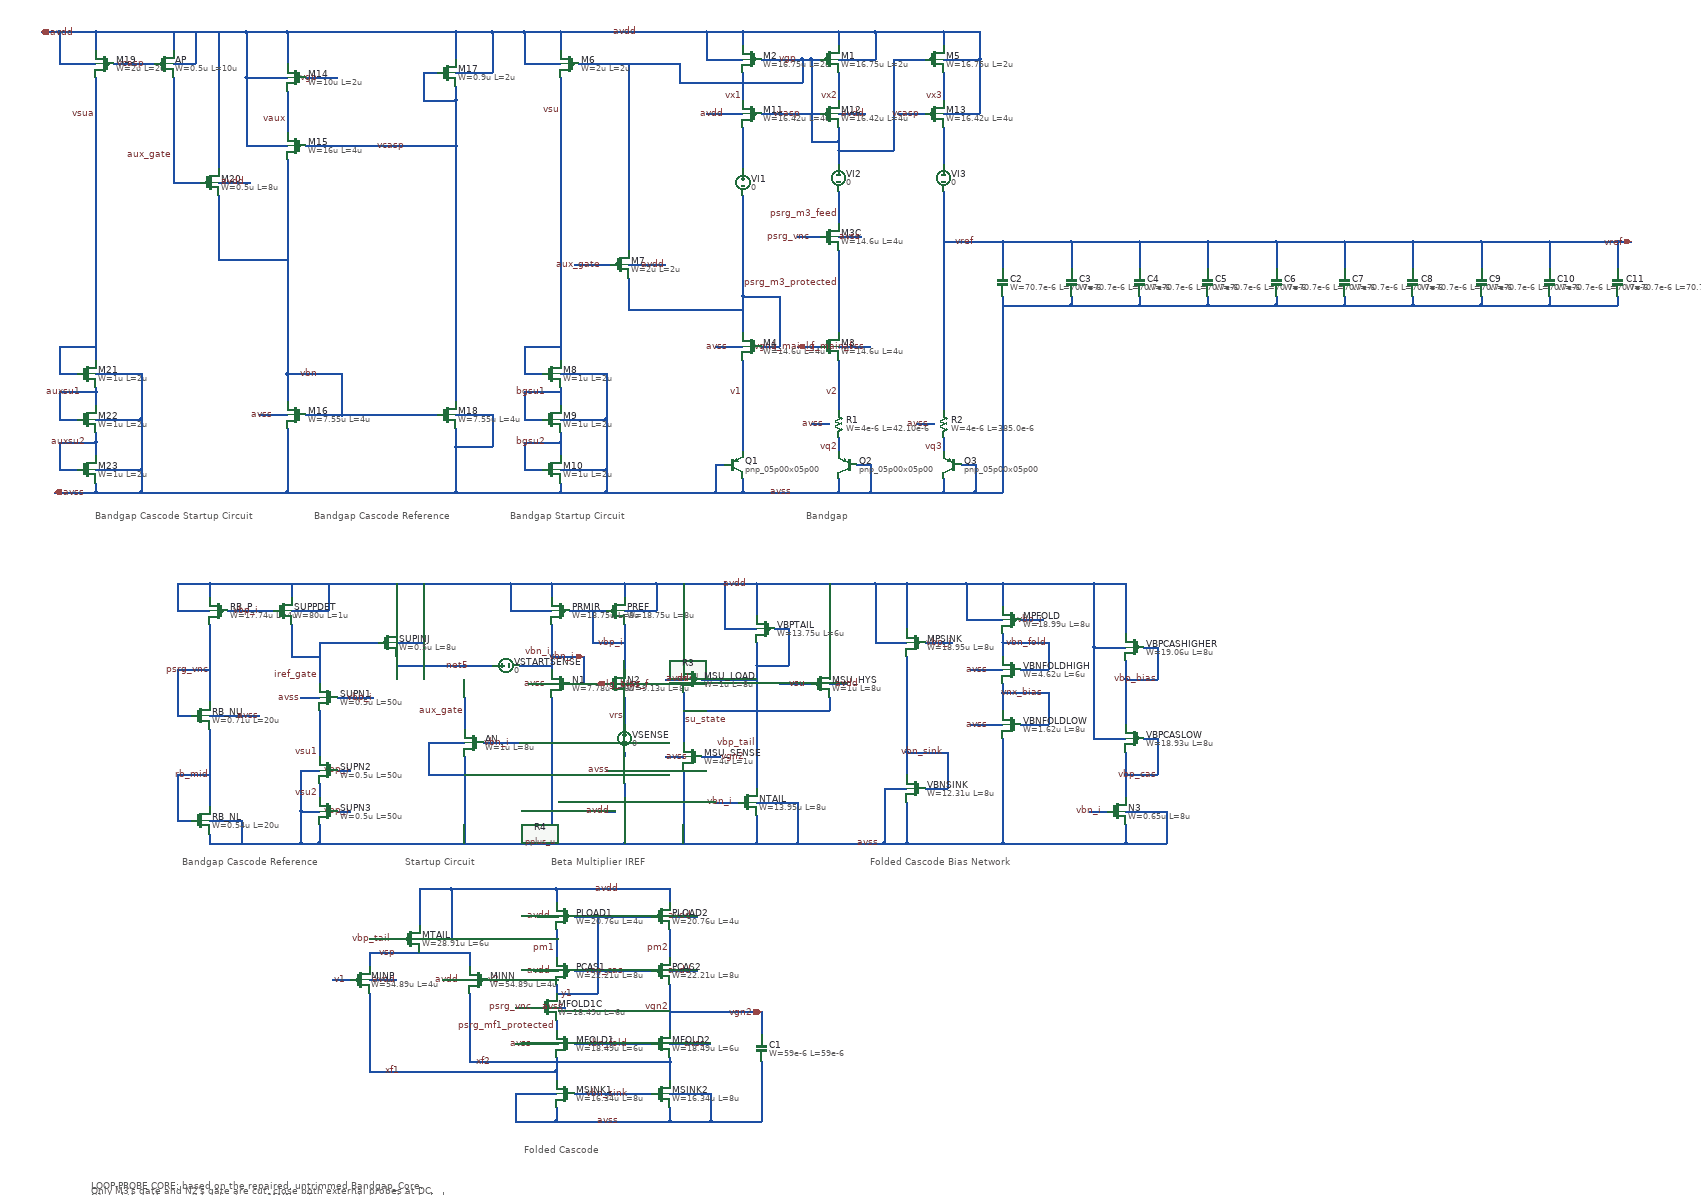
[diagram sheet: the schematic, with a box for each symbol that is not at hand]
v {xschem version=3.4.8RC file_version=1.3}
G {}
K {}
V {}
S {}
F {}
E {}
P 4 1 -1110 -640 {}
T {Bandgap} 570 440 0 0 0.4 0.4 {}
T {Bandgap Startup Circuit} -80 440 0 0 0.4 0.4 {}
T {Bandgap Cascode Reference} -510 440 0 0 0.4 0.4 {}
T {Bandgap Cascode Startup Circuit} -990 440 0 0 0.4 0.4 {}
T {Folded Cascode} -50 1830 0 0 0.4 0.4 {}
T {Folded Cascode Bias Network} 710 1200 0 0 0.4 0.4 {}
T {Beta Multiplier IREF} 10 1200 0 0 0.4 0.4 {}
T {Bandgap Cascode Reference
} -800 1200 0 0 0.4 0.4 {}
T {Startup Circuit} -310 1200 0 0 0.4 0.4 {}
N 580 -550 600 -550 {lab=vgp}
N 640 -550 720 -550 {lab=avdd}
N 720 -610 720 -550 {lab=avdd}
N 640 -610 720 -610 {lab=avdd}
N 640 -610 640 -580 {lab=avdd}
N 350 -550 430 -550 {lab=avdd}
N 350 -610 430 -610 {lab=avdd}
N 430 -610 430 -580 {lab=avdd}
N 350 -610 350 -550 {lab=avdd}
N 870 -550 950 -550 {lab=avdd}
N 870 -610 950 -610 {lab=avdd}
N 510 20 510 80 {lab=vgn1}
N 640 -350 760 -350 {lab=vgp}
N 430 370 430 400 {lab=avss}
N 430 400 640 400 {lab=avss}
N 640 370 640 400 {lab=avss}
N 710 400 870 400 {lab=avss}
N 870 370 870 400 {lab=avss}
N 680 340 710 340 {lab=avss}
N 710 340 710 400 {lab=avss}
N 370 400 430 400 {lab=avss}
N 370 340 370 400 {lab=avss}
N 370 340 390 340 {lab=avss}
N 870 400 940 400 {lab=avss}
N 940 340 940 400 {lab=avss}
N 910 340 940 340 {lab=avss}
N 370 80 430 80 {lab=avss}
N 640 80 710 80 {lab=avss}
N 30 -610 350 -610 {lab=avdd}
N 30 -610 30 -570 {lab=avdd}
N 70 -540 160 -540 {lab=vgp}
N 30 -510 30 -490 {lab=vsu}
N 160 -540 290 -540 {lab=vgp}
N 290 -540 290 -500 {lab=vgp}
N 290 -500 560 -500 {lab=vgp}
N -50 140 -10 140 {lab=vsu}
N -50 80 -50 140 {lab=vsu}
N 30 -170 30 110 {lab=vsu}
N -50 240 -10 240 {lab=bgsu1}
N -50 180 -50 240 {lab=bgsu1}
N -50 180 30 180 {lab=bgsu1}
N 30 180 30 210 {lab=bgsu1}
N -50 350 -10 350 {lab=bgsu2}
N -50 290 -50 350 {lab=bgsu2}
N -50 290 30 290 {lab=bgsu2}
N 30 290 30 320 {lab=bgsu2}
N 30 380 30 400 {lab=avss}
N 130 400 370 400 {lab=avss}
N 130 350 130 400 {lab=avss}
N 30 350 130 350 {lab=avss}
N 30 270 30 290 {lab=bgsu2}
N 30 240 130 240 {lab=avss}
N 130 240 130 350 {lab=avss}
N 130 140 130 240 {lab=avss}
N 30 140 130 140 {lab=avss}
N 30 -490 30 -170 {lab=vsu}
N 430 -610 640 -610 {lab=avdd}
N 870 -610 870 -580 {lab=avdd}
N 720 -610 870 -610 {lab=avdd}
N -50 -540 30 -540 {lab=avdd}
N -50 -610 -50 -540 {lab=avdd}
N -50 -610 30 -610 {lab=avdd}
N 640 110 640 220 {lab=v2}
N 640 280 640 310 {lab=vq2}
N 870 280 870 310 {lab=vq3}
N 810 250 850 250 {lab=avss}
N 580 250 620 250 {lab=avss}
N 430 30 430 50 {lab=vgn1}
N 870 -110 870 220 {lab=vref}
N 950 -610 950 -550 {lab=avdd}
N 430 -520 430 -460 {lab=vx1}
N 350 -430 430 -430 {lab=avdd}
N 640 -520 640 -460 {lab=vx2}
N 470 -430 600 -430 {lab=vcasp}
N 870 -520 870 -460 {lab=vx3}
N 870 -430 950 -430 {lab=avdd}
N 950 -550 950 -430 {lab=avdd}
N 870 -400 870 -320 {lab=#net1}
N 640 -350 640 -320 {lab=vgp}
N 770 -430 830 -430 {lab=vcasp}
N 560 -550 560 -500 {lab=vgp}
N 760 -550 830 -550 {lab=vgp}
N 760 -550 760 -350 {lab=vgp}
N 580 -370 640 -370 {lab=vgp}
N 580 -550 580 -370 {lab=vgp}
N 640 -430 700 -430 {lab=avdd}
N -200 400 30 400 {lab=avss}
N -570 260 -570 400 {lab=avss}
N -660 -510 -570 -510 {lab=avdd}
N -570 -610 -200 -610 {lab=avdd}
N -660 -610 -660 -510 {lab=avdd}
N -570 -610 -570 -540 {lab=avdd}
N -570 -480 -570 -390 {lab=vaux}
N -270 -520 -240 -520 {lab=vcasp}
N -270 -520 -270 -460 {lab=vcasp}
N -270 -460 -200 -460 {lab=vcasp}
N -200 -490 -200 -460 {lab=vcasp}
N -200 -610 -200 -550 {lab=avdd}
N -120 -610 -120 -520 {lab=avdd}
N -200 300 -200 400 {lab=avss}
N -200 230 -120 230 {lab=avss}
N -120 230 -120 300 {lab=avss}
N -200 300 -120 300 {lab=avss}
N -200 -460 -200 -360 {lab=vcasp}
N -570 140 -450 140 {lab=vbn}
N -530 -510 -460 -510 {lab=vgp}
N -120 -610 -50 -610 {lab=avdd}
N -450 230 -240 230 {lab=vbn}
N 30 170 30 180 {lab=bgsu1}
N -570 140 -570 200 {lab=vbn}
N -570 -180 -570 140 {lab=vbn}
N -660 -360 -570 -360 {lab=avdd}
N -660 -510 -660 -360 {lab=avdd}
N -530 -360 -200 -360 {lab=vcasp}
N -990 -610 -990 -570 {lab=avdd}
N -950 -540 -860 -540 {lab=vcasp}
N -990 -510 -990 -490 {lab=vsua}
N -1070 140 -1030 140 {lab=vsua}
N -1070 80 -1070 140 {lab=vsua}
N -990 -170 -990 110 {lab=vsua}
N -1070 240 -1030 240 {lab=auxsu1}
N -1070 180 -1070 240 {lab=auxsu1}
N -1070 180 -990 180 {lab=auxsu1}
N -990 180 -990 210 {lab=auxsu1}
N -1070 350 -1030 350 {lab=auxsu2}
N -1070 290 -1070 350 {lab=auxsu2}
N -1070 290 -990 290 {lab=auxsu2}
N -990 290 -990 320 {lab=auxsu2}
N -890 350 -890 400 {lab=avss}
N -990 350 -890 350 {lab=avss}
N -990 270 -990 290 {lab=auxsu2}
N -990 240 -890 240 {lab=avss}
N -890 240 -890 350 {lab=avss}
N -890 140 -890 240 {lab=avss}
N -990 140 -890 140 {lab=avss}
N -990 -490 -990 -170 {lab=vsua}
N -1070 -540 -990 -540 {lab=avdd}
N -1070 -610 -1070 -540 {lab=avdd}
N -990 170 -990 180 {lab=auxsu1}
N -990 380 -990 400 {lab=avss}
N -890 400 -650 400 {lab=avss}
N -790 -610 -740 -610 {lab=avdd}
N -530 230 -450 230 {lab=vbn}
N -450 140 -450 230 {lab=vbn}
N -630 230 -570 230 {lab=avss}
N -570 -330 -570 -180 {lab=vbn}
N -200 -360 -200 -50 {lab=vcasp}
N 430 110 430 310 {lab=v1}
N 870 -260 870 -110 {lab=vref}
N 470 80 510 80 {lab=vgn1}
N 550 80 600 80 {lab=lg_main_f}
N 640 -370 640 -350 {lab=vgp}
N 640 400 710 400 {lab=avss}
N 30 400 130 400 {lab=avss}
N 470 -550 560 -550 {lab=vgp}
N 640 -400 640 -370 {lab=vgp}
N 560 -550 580 -550 {lab=vgp}
N -660 -610 -570 -610 {lab=avdd}
N -200 -610 -120 -610 {lab=avdd}
N -570 400 -200 400 {lab=avss}
N -200 260 -200 300 {lab=avss}
N -1070 -610 -990 -610 {lab=avdd}
N -990 400 -890 400 {lab=avss}
N -990 -610 -790 -610 {lab=avdd}
N -200 -520 -120 -520 {lab=avdd}
N -1070 80 -990 80 {lab=vsua}
N -200 -50 -200 200 {lab=vcasp}
N -50 80 30 80 {lab=vsu}
N 510 -30 510 20 {lab=vgn1}
N 430 -30 510 -30 {lab=vgn1}
N 430 10 430 30 {lab=vgn1}
N 430 -30 430 10 {lab=vgn1}
N 430 -250 430 -30 {lab=vgn1}
N 430 -400 430 -310 {lab=#net2}
N 870 -150 950 -150 {lab=vref}
N 640 -260 640 -190 {lab=psrg_m3_feed}
N 640 -160 690 -160 {lab=avss}
N 550 -160 600 -160 {lab=psrg_vnc}
N 640 -130 640 50 {lab=psrg_m3_protected}
N 1000 -150 1000 -90 {lab=vref}
N 950 -150 1000 -150 {lab=vref}
N 1000 -30 1000 400 {lab=avss}
N 940 400 1000 400 {lab=avss}
N 1150 -30 1150 -10 {lab=avss}
N 1000 -10 1150 -10 {lab=avss}
N 1150 -150 1150 -90 {lab=vref}
N 1000 -150 1150 -150 {lab=vref}
N 1300 -30 1300 -10 {lab=avss}
N 1150 -10 1300 -10 {lab=avss}
N 1300 -150 1300 -90 {lab=vref}
N 1150 -150 1300 -150 {lab=vref}
N 1450 -30 1450 -10 {lab=avss}
N 1300 -10 1450 -10 {lab=avss}
N 1450 -150 1450 -90 {lab=vref}
N 1300 -150 1450 -150 {lab=vref}
N 1600 -30 1600 -10 {lab=avss}
N 1450 -10 1600 -10 {lab=avss}
N 1600 -150 1600 -90 {lab=vref}
N 1450 -150 1600 -150 {lab=vref}
N 1750 -30 1750 -10 {lab=avss}
N 1600 -10 1750 -10 {lab=avss}
N 1750 -150 1750 -90 {lab=vref}
N 1600 -150 1750 -150 {lab=vref}
N 1900 -30 1900 -10 {lab=avss}
N 1750 -10 1900 -10 {lab=avss}
N 1900 -150 1900 -90 {lab=vref}
N 1750 -150 1900 -150 {lab=vref}
N 2050 -30 2050 -10 {lab=avss}
N 1900 -10 2050 -10 {lab=avss}
N 2050 -150 2050 -90 {lab=vref}
N 1900 -150 2050 -150 {lab=vref}
N 2200 -30 2200 -10 {lab=avss}
N 2050 -10 2200 -10 {lab=avss}
N 2200 -150 2200 -90 {lab=vref}
N 2050 -150 2200 -150 {lab=vref}
N 2350 -30 2350 -10 {lab=avss}
N 2200 -10 2350 -10 {lab=avss}
N 2350 -150 2350 -90 {lab=vref}
N 2200 -150 2350 -150 {lab=vref}
N -1110 -610 -1070 -610 {lab=avdd}
N -1080 400 -990 400 {lab=avss}
N -280 1380 -210 1380 {lab=avdd}
N -390 1380 -320 1380 {lab=vbp_tail}
N -390 1410 -390 1440 {lab=vsp}
N -170 1410 -170 1440 {lab=vsp}
N -390 1410 -170 1410 {lab=vsp}
N -390 1470 -330 1470 {lab=avdd}
N -230 1470 -170 1470 {lab=avdd}
N -470 1470 -430 1470 {lab=v1}
N -130 1470 -90 1470 {lab=v2}
N 20 1670 20 1690 {lab=xf1}
N 60 1610 230 1610 {lab=vbn_fold}
N 60 1720 230 1720 {lab=vbn_sink}
N 270 1650 270 1690 {lab=xf2}
N -70 1720 20 1720 {lab=avss}
N -70 1720 -70 1780 {lab=avss}
N 270 1780 360 1780 {lab=avss}
N 360 1720 360 1780 {lab=avss}
N 270 1720 360 1720 {lab=avss}
N 270 1750 270 1780 {lab=avss}
N 20 1750 20 1780 {lab=avss}
N -70 1610 20 1610 {lab=avss}
N 270 1610 360 1610 {lab=avss}
N -390 1500 -390 1670 {lab=xf1}
N -390 1670 20 1670 {lab=xf1}
N -170 1500 -170 1650 {lab=xf2}
N -170 1650 270 1650 {lab=xf2}
N 20 1360 20 1420 {lab=pm1}
N 270 1360 270 1420 {lab=pm2}
N 270 1480 270 1580 {lab=vgn2}
N 60 1450 230 1450 {lab=vbp_cas}
N 110 1330 230 1330 {lab=y1}
N 270 1270 270 1300 {lab=avdd}
N 20 1270 270 1270 {lab=avdd}
N 20 1270 20 1300 {lab=avdd}
N -30 1450 20 1450 {lab=avdd}
N -20 1330 20 1330 {lab=avdd}
N 270 1330 330 1330 {lab=avdd}
N 270 1450 330 1450 {lab=avdd}
N -280 1270 -280 1350 {lab=avdd}
N -210 1270 20 1270 {lab=avdd}
N 110 1330 110 1500 {lab=y1}
N -210 1270 -210 1380 {lab=avdd}
N 20 1500 110 1500 {lab=y1}
N 460 600 460 670 {lab=avdd}
N 390 700 460 700 {lab=avdd}
N 390 600 390 700 {lab=avdd}
N 390 600 460 600 {lab=avdd}
N 460 730 460 780 {lab=vbp_tail}
N 460 780 530 780 {lab=vbp_tail}
N 530 700 530 780 {lab=vbp_tail}
N 500 700 530 700 {lab=vbp_tail}
N 460 780 460 1050 {lab=vbp_tail}
N 460 1110 460 1170 {lab=avss}
N 790 1080 790 1170 {lab=avss}
N 740 1050 790 1050 {lab=avss}
N 740 1050 740 1170 {lab=avss}
N 790 760 790 970 {lab=vbn_sink}
N 790 600 790 700 {lab=avdd}
N 720 600 790 600 {lab=avdd}
N 830 1050 880 1050 {lab=vbn_sink}
N 880 970 880 1050 {lab=vbn_sink}
N 790 970 880 970 {lab=vbn_sink}
N 790 970 790 1020 {lab=vbn_sink}
N 1000 730 1000 760 {lab=vbn_fold}
N 1000 730 1100 730 {lab=vbn_fold}
N 1100 730 1100 790 {lab=vbn_fold}
N 1040 790 1100 790 {lab=vbn_fold}
N 930 790 1000 790 {lab=avss}
N 1000 710 1000 730 {lab=vbn_fold}
N 1000 600 1000 650 {lab=avdd}
N 920 600 1000 600 {lab=avdd}
N 1040 910 1100 910 {lab=vnx_bias}
N 930 910 1000 910 {lab=avss}
N 1000 840 1000 880 {lab=vnx_bias}
N 1000 840 1100 840 {lab=vnx_bias}
N 1100 840 1100 910 {lab=vnx_bias}
N 1000 940 1000 1170 {lab=avss}
N 790 1170 1000 1170 {lab=avss}
N 1270 1130 1270 1170 {lab=avss}
N 1270 1020 1270 1070 {lab=vbp_cas}
N 1000 1170 1270 1170 {lab=avss}
N 1200 940 1270 940 {lab=avdd}
N 1270 970 1270 1020 {lab=vbp_cas}
N 1310 940 1340 940 {lab=vbp_cas}
N 1200 740 1270 740 {lab=avdd}
N 1270 810 1270 910 {lab=vbp_bias}
N 1310 740 1340 740 {lab=vbp_bias}
N 1200 600 1270 600 {lab=avdd}
N 1270 600 1270 710 {lab=avdd}
N 1270 1020 1340 1020 {lab=vbp_cas}
N 1340 940 1340 1020 {lab=vbp_cas}
N 1270 810 1340 810 {lab=vbp_bias}
N 1340 740 1340 810 {lab=vbp_bias}
N 1200 740 1200 940 {lab=avdd}
N 1200 600 1200 740 {lab=avdd}
N 550 1080 550 1170 {lab=avss}
N 460 1080 550 1080 {lab=avss}
N 370 1080 420 1080 {lab=vbn_i}
N 1270 1170 1360 1170 {lab=avss}
N 1360 1100 1360 1170 {lab=avss}
N 1270 1100 1360 1100 {lab=avss}
N 1190 1100 1230 1100 {lab=vbn_i}
N 720 730 790 730 {lab=avdd}
N 720 600 720 730 {lab=avdd}
N 830 730 890 730 {lab=vbp_i}
N 920 680 1000 680 {lab=avdd}
N 920 600 920 680 {lab=avdd}
N 1040 680 1090 680 {lab=vbp_i}
N -80 660 10 660 {lab=avdd}
N -80 600 -80 660 {lab=avdd}
N 20 1780 270 1780 {lab=avss}
N -70 1780 20 1780 {lab=avss}
N 20 1640 20 1670 {lab=xf1}
N 270 1640 270 1650 {lab=xf2}
N 60 1330 110 1330 {lab=y1}
N -280 1270 -210 1270 {lab=avdd}
N 20 1480 20 1500 {lab=y1}
N 740 1170 790 1170 {lab=avss}
N 670 1170 740 1170 {lab=avss}
N 1000 820 1000 840 {lab=vnx_bias}
N 1270 770 1270 810 {lab=vbp_bias}
N 1000 600 1200 600 {lab=avdd}
N 170 1170 460 1170 {lab=avss}
N 460 1170 550 1170 {lab=avss}
N 580 600 720 600 {lab=avdd}
N 790 600 920 600 {lab=avdd}
N 240 600 390 600 {lab=avdd}
N 10 600 10 630 {lab=avdd}
N 170 600 170 630 {lab=avdd}
N 100 660 130 660 {lab=vbp_i}
N 110 820 130 820 {lab=lg_bias_f}
N -40 820 10 820 {lab=avss}
N 170 820 220 820 {lab=avss}
N 100 730 170 730 {lab=vbp_i}
N 100 660 100 730 {lab=vbp_i}
N 10 850 10 1170 {lab=avss}
N 10 1170 170 1170 {lab=avss}
N -80 600 10 600 {lab=avdd}
N 10 600 170 600 {lab=avdd}
N 50 820 80 820 {lab=vbn_i}
N 170 690 170 730 {lab=vbp_i}
N 50 660 100 660 {lab=vbp_i}
N 10 760 10 780 {lab=vbn_i}
N 170 660 240 660 {lab=avdd}
N 240 600 240 660 {lab=avdd}
N 10 780 10 790 {lab=vbn_i}
N 170 730 170 790 {lab=vbp_i}
N 170 1130 170 1170 {lab=avss}
N 170 1040 170 1070 {lab=#net3}
N 130 1010 150 1010 {lab=avss}
N 130 1100 150 1100 {lab=avdd}
N 80 760 80 820 {lab=vbn_i}
N 10 760 80 760 {lab=vbn_i}
N 170 850 170 910 {lab=vrs}
N 170 970 170 980 {lab=#net4}
N -500 950 -500 980 {lab=vsu1}
N -500 1040 -500 1070 {lab=vsu2}
N -500 1170 -100 1170 {lab=avss}
N -500 1130 -500 1170 {lab=avss}
N -540 1100 -500 1100 {lab=avss}
N -540 1100 -540 1170 {lab=avss}
N -540 1170 -500 1170 {lab=avss}
N -540 1010 -540 1100 {lab=avss}
N -540 1010 -500 1010 {lab=avss}
N -240 600 -190 600 {lab=avdd}
N -460 1010 -430 1010 {lab=vbp_i}
N -460 1100 -430 1100 {lab=vbp_i}
N -60 780 10 780 {lab=vbn_i}
N 170 600 240 600 {lab=avdd}
N 10 690 10 760 {lab=vbn_i}
N -300 600 -240 600 {lab=avdd}
N 20 1530 40 1530 {lab=avss}
N 20 1560 20 1580 {lab=psrg_mf1_protected}
N -70 1530 -20 1530 {lab=psrg_vnc}
N -810 890 -780 890 {lab=psrg_vnc}
N -810 790 -810 890 {lab=psrg_vnc}
N -810 790 -740 790 {lab=psrg_vnc}
N -740 920 -740 1090 {lab=rb_mid}
N -810 1120 -780 1120 {lab=rb_mid}
N -810 1020 -810 1120 {lab=rb_mid}
N -810 1020 -740 1020 {lab=rb_mid}
N 270 1540 470 1540 {lab=vgn2}
N 470 1540 470 1590 {lab=vgn2}
N 470 1650 470 1780 {lab=avss}
N 360 1780 470 1780 {lab=avss}
N 300 840 300 870 {lab=su_state}
N 340 810 380 810 {lab=vbp_tail}
N 300 750 300 780 {lab=avdd}
N 260 810 300 810 {lab=avdd}
N 620 850 620 880 {lab=su_state}
N 540 820 580 820 {lab=vsu}
N 620 760 620 790 {lab=avdd}
N 620 820 660 820 {lab=avdd}
N 300 920 300 950 {lab=su_state}
N 340 980 380 980 {lab=vgn2}
N 300 1010 300 1040 {lab=avss}
N 260 980 300 980 {lab=avss}
N -740 890 -630 890 {lab=avss}
N -740 1150 -740 1170 {lab=avss}
N -740 1120 -670 1120 {lab=avss}
N -670 1120 -670 1170 {lab=avss}
N 300 870 300 920 {lab=su_state}
N 300 600 300 750 {lab=avdd}
N 300 1040 300 1170 {lab=avss}
N 380 810 460 810 {lab=vbp_tail}
N -190 600 -90 600 {lab=avdd}
N -90 600 -80 600 {lab=avdd}
N -100 1170 10 1170 {lab=avss}
N 510 820 540 820 {lab=vsu}
N 2350 -150 2380 -150 {lab=vref}
N -720 -250 -720 -180 {lab=vbn}
N -720 -380 -720 -310 {lab=avdd}
N -680 660 -600 660 {lab=vbp_i}
N -500 800 -500 820 {lab=iref_gate}
N -460 850 -380 850 {lab=vbp_i}
N -500 880 -500 950 {lab=vsu1}
N -450 730 -370 730 {lab=iref_gate}
N -330 630 -330 700 {lab=avdd}
N 180 -70 180 0 {lab=vgn1}
N 60 -100 140 -100 {lab=aux_gate}
N 180 -200 180 -130 {lab=vgp}
N -820 -510 -820 -440 {lab=aux_gate}
N -180 850 -180 920 {lab=aux_gate}
N -140 950 -60 950 {lab=vbn_i}
N -180 980 -180 1050 {lab=avss}
N -820 -540 -770 -540 {lab=avdd}
N -770 -610 -770 -540 {lab=avdd}
N -820 -610 -820 -570 {lab=avdd}
N -540 850 -500 850 {lab=avss}
N -500 730 -450 730 {lab=iref_gate}
N -500 730 -500 800 {lab=iref_gate}
N -330 600 -330 630 {lab=avdd}
N -330 730 -270 730 {lab=avdd}
N -270 600 -270 730 {lab=avdd}
N -330 780 -120 780 {lab=net5}
N -330 760 -330 780 {lab=net5}
N -740 1170 -540 1170 {lab=avss}
N 460 600 580 600 {lab=avdd}
N 550 1170 670 1170 {lab=avss}
N 620 610 620 760 {lab=avdd}
N 620 600 620 610 {lab=avdd}
N 300 880 620 880 {lab=su_state}
N -740 -610 -660 -610 {lab=avdd}
N -650 400 -570 400 {lab=avss}
N -820 -280 -760 -280 {lab=aux_gate}
N -820 -440 -820 -280 {lab=aux_gate}
N -720 -610 -720 -380 {lab=avdd}
N -720 -280 -650 -280 {lab=avdd}
N 180 0 430 0 {lab=vgn1}
N 180 -540 180 -200 {lab=vgp}
N -180 1050 -180 1170 {lab=avss}
N -260 950 -180 950 {lab=avss}
N -260 950 -260 1020 {lab=avss}
N -260 1020 -180 1020 {lab=avss}
N -720 -180 -720 -110 {lab=vbn}
N -720 -110 -570 -110 {lab=vbn}
N -560 600 -560 630 {lab=avdd}
N -560 660 -480 660 {lab=avdd}
N -480 600 -480 660 {lab=avdd}
N -560 690 -560 760 {lab=iref_gate}
N -740 600 -300 600 {lab=avdd}
N -740 600 -740 630 {lab=avdd}
N -560 760 -500 760 {lab=iref_gate}
N -740 690 -740 860 {lab=psrg_vnc}
N -700 660 -680 660 {lab=vbp_i}
N -810 660 -740 660 {lab=avdd}
N -810 600 -810 660 {lab=avdd}
N -810 600 -740 600 {lab=avdd}
N 180 -100 260 -100 {lab=#net6}
C {symbols/pnp_05p00x05p00.sym} 890 340 0 1 {name=Q3
model=pnp_05p00x05p00
spiceprefix=X
m=1}
C {symbols/pnp_05p00x05p00.sym} 660 340 0 1 {name=Q2
model=pnp_05p00x05p00
spiceprefix=X
m=8}
C {symbols/pnp_05p00x05p00.sym} 410 340 0 0 {name=Q1
model=pnp_05p00x05p00
spiceprefix=X
m=1}
C {lab_wire.sym} 400 80 0 0 {name=p1 sig_type=std_logic lab=avss
}
C {lab_wire.sym} 700 80 0 0 {name=p2 sig_type=std_logic lab=avss
}
C {lab_wire.sym} 540 400 0 0 {name=p3 sig_type=std_logic lab=avss
}
C {symbols/nfet_03v3.sym} 10 240 0 0 {name=M9
L=2u
W=1u
nf=1
mult=1
ad="'int((nf+1)/2) * W/nf * 0.18u'"
pd="'2*int((nf+1)/2) * (W/nf + 0.18u)'"
as="'int((nf+2)/2) * W/nf * 0.18u'"
ps="'2*int((nf+2)/2) * (W/nf + 0.18u)'"
nrd="'0.18u / W'" nrs="'0.18u / W'"
sa=0 sb=0 sd=0
model=nfet_03v3
spiceprefix=X
}
C {symbols/nfet_03v3.sym} 10 350 0 0 {name=M10
L=2u
W=1u
nf=1
mult=1
ad="'int((nf+1)/2) * W/nf * 0.18u'"
pd="'2*int((nf+1)/2) * (W/nf + 0.18u)'"
as="'int((nf+2)/2) * W/nf * 0.18u'"
ps="'2*int((nf+2)/2) * (W/nf + 0.18u)'"
nrd="'0.18u / W'" nrs="'0.18u / W'"
sa=0 sb=0 sd=0
model=nfet_03v3
spiceprefix=X
}
C {lab_wire.sym} 200 -610 0 0 {name=p4 sig_type=std_logic lab=avdd
}
C {symbols/ppolyf_u_1k.sym} 640 250 0 0 {name=R1
W=4e-6
L=42.10e-6
model=ppolyf_u_1k
spiceprefix=X
m=1}
C {symbols/ppolyf_u_1k.sym} 870 250 0 0 {name=R2
W=4e-6
L=385.0e-6
model=ppolyf_u_1k
spiceprefix=X
m=1}
C {lab_wire.sym} 610 250 0 0 {name=p6 sig_type=std_logic lab=avss
}
C {lab_wire.sym} 840 250 0 0 {name=p7 sig_type=std_logic lab=avss
}
C {lab_wire.sym} 550 -550 0 0 {name=p9 sig_type=std_logic lab=vgp
}
C {lab_wire.sym} 510 80 0 0 {name=p10 sig_type=std_logic lab=vgn1
}
C {lab_wire.sym} 30 -440 0 0 {name=p11 sig_type=std_logic lab=vsu
}
C {lab_wire.sym} 430 180 0 0 {name=p12 sig_type=std_logic lab=v1
}
C {lab_wire.sym} 640 180 0 0 {name=p13 sig_type=std_logic lab=v2
}
C {lab_wire.sym} 640 300 0 0 {name=p14 sig_type=std_logic lab=vq2
}
C {lab_wire.sym} 870 300 0 0 {name=p17 sig_type=std_logic lab=vq3
}
C {vsource.sym} 430 -280 0 0 {name=VI1 value=0 savecurrent=false}
C {vsource.sym} 640 -290 0 0 {name=VI2 value=0 savecurrent=false}
C {vsource.sym} 870 -290 0 0 {name=VI3 value=0 savecurrent=false}
C {lab_wire.sym} 390 -430 0 0 {name=p18 sig_type=std_logic lab=avdd
}
C {lab_wire.sym} 560 -430 0 0 {name=p19 sig_type=std_logic lab=vcasp}
C {lab_wire.sym} 820 -430 0 0 {name=p20 sig_type=std_logic lab=vcasp}
C {lab_wire.sym} 700 -430 0 0 {name=p23 sig_type=std_logic lab=avdd
}
C {lab_wire.sym} 430 -470 0 0 {name=p24 sig_type=std_logic lab=vx1}
C {lab_wire.sym} 640 -470 0 0 {name=p25 sig_type=std_logic lab=vx2}
C {lab_wire.sym} 870 -470 0 0 {name=p26 sig_type=std_logic lab=vx3}
C {lab_wire.sym} -500 140 0 0 {name=p21 sig_type=std_logic lab=vbn
}
C {lab_wire.sym} -310 -360 0 0 {name=p27 sig_type=std_logic lab=vcasp
}
C {lab_wire.sym} -500 -510 0 0 {name=p28 sig_type=std_logic lab=vgp
}
C {lab_wire.sym} -570 -420 0 0 {name=p22 sig_type=std_logic lab=vaux
}
C {symbols/nfet_03v3.sym} -1010 240 0 0 {name=M22
L=2u
W=1u
nf=1
mult=1
ad="'int((nf+1)/2) * W/nf * 0.18u'"
pd="'2*int((nf+1)/2) * (W/nf + 0.18u)'"
as="'int((nf+2)/2) * W/nf * 0.18u'"
ps="'2*int((nf+2)/2) * (W/nf + 0.18u)'"
nrd="'0.18u / W'" nrs="'0.18u / W'"
sa=0 sb=0 sd=0
model=nfet_03v3
spiceprefix=X
}
C {symbols/nfet_03v3.sym} -1010 350 0 0 {name=M23
L=2u
W=1u
nf=1
mult=1
ad="'int((nf+1)/2) * W/nf * 0.18u'"
pd="'2*int((nf+1)/2) * (W/nf + 0.18u)'"
as="'int((nf+2)/2) * W/nf * 0.18u'"
ps="'2*int((nf+2)/2) * (W/nf + 0.18u)'"
nrd="'0.18u / W'" nrs="'0.18u / W'"
sa=0 sb=0 sd=0
model=nfet_03v3
spiceprefix=X
}
C {lab_wire.sym} -990 -430 0 0 {name=p29 sig_type=std_logic lab=vsua}
C {lab_wire.sym} -600 230 0 0 {name=p30 sig_type=std_logic lab=avss
}
C {lab_wire.sym} -880 -540 0 0 {name=p31 sig_type=std_logic lab=vcasp}
C {lab_wire.sym} 590 80 0 0 {name=p32 sig_type=std_logic lab=lg_main_f
}
C {symbols/pfet_05v0.sym} 450 -430 0 1 {name=M11
L=4u
W=16.42u
nf=1
mult=5
m=5
ad="'int((nf+1)/2) * W/nf * 0.18u'"
pd="'2*int((nf+1)/2) * (W/nf + 0.18u)'"
as="'int((nf+2)/2) * W/nf * 0.18u'"
ps="'2*int((nf+2)/2) * (W/nf + 0.18u)'"
nrd="'0.18u / W'" nrs="'0.18u / W'"
sa=0 sb=0 sd=0
model=pfet_05v0
spiceprefix=X
}
C {symbols/pfet_05v0.sym} 620 -430 0 0 {name=M12
L=4u
W=16.42u
nf=1
mult=5
m=5
ad="'int((nf+1)/2) * W/nf * 0.18u'"
pd="'2*int((nf+1)/2) * (W/nf + 0.18u)'"
as="'int((nf+2)/2) * W/nf * 0.18u'"
ps="'2*int((nf+2)/2) * (W/nf + 0.18u)'"
nrd="'0.18u / W'" nrs="'0.18u / W'"
sa=0 sb=0 sd=0
model=pfet_05v0
spiceprefix=X
}
C {symbols/pfet_05v0.sym} 850 -430 0 0 {name=M13
L=4u
W=16.42u
nf=1
mult=5
m=5
ad="'int((nf+1)/2) * W/nf * 0.18u'"
pd="'2*int((nf+1)/2) * (W/nf + 0.18u)'"
as="'int((nf+2)/2) * W/nf * 0.18u'"
ps="'2*int((nf+2)/2) * (W/nf + 0.18u)'"
nrd="'0.18u / W'" nrs="'0.18u / W'"
sa=0 sb=0 sd=0
model=pfet_05v0
spiceprefix=X
}
C {symbols/nfet_05v0.sym} 450 80 0 1 {name=M4
L=4u
W=14.6u
nf=1
mult=2
m=2
ad="'int((nf+1)/2) * W/nf * 0.18u'"
pd="'2*int((nf+1)/2) * (W/nf + 0.18u)'"
as="'int((nf+2)/2) * W/nf * 0.18u'"
ps="'2*int((nf+2)/2) * (W/nf + 0.18u)'"
nrd="'0.18u / W'" nrs="'0.18u / W'"
sa=0 sb=0 sd=0
model=nfet_05v0
spiceprefix=X
}
C {symbols/nfet_05v0.sym} 620 80 0 0 {name=M3
L=4u
W=14.6u
nf=1
mult=2
m=2
ad="'int((nf+1)/2) * W/nf * 0.18u'"
pd="'2*int((nf+1)/2) * (W/nf + 0.18u)'"
as="'int((nf+2)/2) * W/nf * 0.18u'"
ps="'2*int((nf+2)/2) * (W/nf + 0.18u)'"
nrd="'0.18u / W'" nrs="'0.18u / W'"
sa=0 sb=0 sd=0
model=nfet_05v0
spiceprefix=X
}
C {symbols/nfet_05v0.sym} -550 230 0 1 {name=M16
L=4u
W=7.55u
nf=1
mult=1
ad="'int((nf+1)/2) * W/nf * 0.18u'"
pd="'2*int((nf+1)/2) * (W/nf + 0.18u)'"
as="'int((nf+2)/2) * W/nf * 0.18u'"
ps="'2*int((nf+2)/2) * (W/nf + 0.18u)'"
nrd="'0.18u / W'" nrs="'0.18u / W'"
sa=0 sb=0 sd=0
model=nfet_05v0
spiceprefix=X
}
C {symbols/nfet_05v0.sym} -220 230 0 0 {name=M18
L=4u
W=7.55u
nf=1
mult=1
ad="'int((nf+1)/2) * W/nf * 0.18u'"
pd="'2*int((nf+1)/2) * (W/nf + 0.18u)'"
as="'int((nf+2)/2) * W/nf * 0.18u'"
ps="'2*int((nf+2)/2) * (W/nf + 0.18u)'"
nrd="'0.18u / W'" nrs="'0.18u / W'"
sa=0 sb=0 sd=0
model=nfet_05v0
spiceprefix=X
}
C {symbols/pfet_05v0.sym} -550 -360 0 1 {name=M15
L=4u
W=16u
nf=1
mult=1
m=1
ad="'int((nf+1)/2) * W/nf * 0.18u'"
pd="'2*int((nf+1)/2) * (W/nf + 0.18u)'"
as="'int((nf+2)/2) * W/nf * 0.18u'"
ps="'2*int((nf+2)/2) * (W/nf + 0.18u)'"
nrd="'0.18u / W'" nrs="'0.18u / W'"
sa=0 sb=0 sd=0
model=pfet_05v0
spiceprefix=X
}
C {symbols/pfet_05v0.sym} -220 -520 0 0 {name=M17
L=2u
W=0.9u
nf=1
mult=1
m=1
ad="'int((nf+1)/2) * W/nf * 0.18u'"
pd="'2*int((nf+1)/2) * (W/nf + 0.18u)'"
as="'int((nf+2)/2) * W/nf * 0.18u'"
ps="'2*int((nf+2)/2) * (W/nf + 0.18u)'"
nrd="'0.18u / W'" nrs="'0.18u / W'"
sa=0 sb=0 sd=0
model=pfet_05v0
spiceprefix=X
}
C {lab_wire.sym} 0 180 0 0 {name=p84 sig_type=std_logic lab=bgsu1
}
C {lab_wire.sym} 0 290 0 0 {name=p85 sig_type=std_logic lab=bgsu2
}
C {lab_wire.sym} -1020 180 0 0 {name=p86 sig_type=std_logic lab=auxsu1
}
C {lab_wire.sym} -1010 290 0 0 {name=p87 sig_type=std_logic lab=auxsu2
}
C {symbols/pfet_05v0.sym} 50 -540 0 1 {name=M6
L=2u
W=2u
nf=1
mult=1
ad="'int((nf+1)/2) * W/nf * 0.18u'"
pd="'2*int((nf+1)/2) * (W/nf + 0.18u)'"
as="'int((nf+2)/2) * W/nf * 0.18u'"
ps="'2*int((nf+2)/2) * (W/nf + 0.18u)'"
nrd="'0.18u / W'" nrs="'0.18u / W'"
sa=0 sb=0 sd=0
model=pfet_05v0
spiceprefix=X
}
C {symbols/pfet_05v0.sym} -970 -540 0 1 {name=M19
L=2u
W=2u
nf=1
mult=1
ad="'int((nf+1)/2) * W/nf * 0.18u'"
pd="'2*int((nf+1)/2) * (W/nf + 0.18u)'"
as="'int((nf+2)/2) * W/nf * 0.18u'"
ps="'2*int((nf+2)/2) * (W/nf + 0.18u)'"
nrd="'0.18u / W'" nrs="'0.18u / W'"
sa=0 sb=0 sd=0
model=pfet_05v0
spiceprefix=X
}
C {symbols/nfet_05v0.sym} 10 140 0 0 {name=M8
L=2u
W=1u
nf=1
mult=1
ad="'int((nf+1)/2) * W/nf * 0.18u'"
pd="'2*int((nf+1)/2) * (W/nf + 0.18u)'"
as="'int((nf+2)/2) * W/nf * 0.18u'"
ps="'2*int((nf+2)/2) * (W/nf + 0.18u)'"
nrd="'0.18u / W'" nrs="'0.18u / W'"
sa=0 sb=0 sd=0
model=nfet_05v0
spiceprefix=X
}
C {symbols/nfet_05v0.sym} -1010 140 0 0 {name=M21
L=2u
W=1u
nf=1
mult=1
ad="'int((nf+1)/2) * W/nf * 0.18u'"
pd="'2*int((nf+1)/2) * (W/nf + 0.18u)'"
as="'int((nf+2)/2) * W/nf * 0.18u'"
ps="'2*int((nf+2)/2) * (W/nf + 0.18u)'"
nrd="'0.18u / W'" nrs="'0.18u / W'"
sa=0 sb=0 sd=0
model=nfet_05v0
spiceprefix=X
}
C {symbols/pfet_05v0.sym} 450 -550 0 1 {name=M2
L=2u
W=16.75u
nf=1
mult=6
m=6
ad="'int((nf+1)/2) * W/nf * 0.18u'"
pd="'2*int((nf+1)/2) * (W/nf + 0.18u)'"
as="'int((nf+2)/2) * W/nf * 0.18u'"
ps="'2*int((nf+2)/2) * (W/nf + 0.18u)'"
nrd="'0.18u / W'" nrs="'0.18u / W'"
sa=0 sb=0 sd=0
model=pfet_05v0
spiceprefix=X
}
C {symbols/pfet_05v0.sym} 620 -550 0 0 {name=M1
L=2u
W=16.75u
nf=1
mult=6
m=6
ad="'int((nf+1)/2) * W/nf * 0.18u'"
pd="'2*int((nf+1)/2) * (W/nf + 0.18u)'"
as="'int((nf+2)/2) * W/nf * 0.18u'"
ps="'2*int((nf+2)/2) * (W/nf + 0.18u)'"
nrd="'0.18u / W'" nrs="'0.18u / W'"
sa=0 sb=0 sd=0
model=pfet_05v0
spiceprefix=X
}
C {symbols/pfet_05v0.sym} 850 -550 0 0 {name=M5
L=2u
W=16.75u
nf=1
mult=6
m=6
ad="'int((nf+1)/2) * W/nf * 0.18u'"
pd="'2*int((nf+1)/2) * (W/nf + 0.18u)'"
as="'int((nf+2)/2) * W/nf * 0.18u'"
ps="'2*int((nf+2)/2) * (W/nf + 0.18u)'"
nrd="'0.18u / W'" nrs="'0.18u / W'"
sa=0 sb=0 sd=0
model=pfet_05v0
spiceprefix=X
}
C {symbols/pfet_05v0.sym} -550 -510 0 1 {name=M14
L=2u
W=10u
nf=1
mult=2
m=2
ad="'int((nf+1)/2) * W/nf * 0.18u'"
pd="'2*int((nf+1)/2) * (W/nf + 0.18u)'"
as="'int((nf+2)/2) * W/nf * 0.18u'"
ps="'2*int((nf+2)/2) * (W/nf + 0.18u)'"
nrd="'0.18u / W'" nrs="'0.18u / W'"
sa=0 sb=0 sd=0
model=pfet_05v0
spiceprefix=X
}
C {symbols/nfet_05v0.sym} 620 -160 0 0 {name=M3C
L=4u
W=14.6u
nf=1
mult=2
m=2
ad="'int((nf+1)/2) * W/nf * 0.18u'"
pd="'2*int((nf+1)/2) * (W/nf + 0.18u)'"
as="'int((nf+2)/2) * W/nf * 0.18u'"
ps="'2*int((nf+2)/2) * (W/nf + 0.18u)'"
nrd="'0.18u / W'" nrs="'0.18u / W'"
sa=0 sb=0 sd=0
model=nfet_05v0
spiceprefix=X
}
C {lab_wire.sym} 640 -210 0 0 {name=psrg5_label0 sig_type=std_logic lab=psrg_m3_feed}
C {lab_wire.sym} 640 -60 0 0 {name=psrg5_label2 sig_type=std_logic lab=psrg_m3_protected}
C {lab_wire.sym} 690 -160 0 0 {name=psrg5_label3 sig_type=std_logic lab=avss}
C {lab_wire.sym} 940 -150 0 0 {name=p8 sig_type=std_logic lab=vref
}
C {lab_wire.sym} 580 -160 0 0 {name=psrg4 sig_type=std_logic lab=psrg_vnc}
C {symbols/cap_mim_2f0fF.sym} 1000 -60 0 0 {name=C2
W=70.7e-6
L=70.7e-6
model=cap_mim_2f0fF
spiceprefix=X
m=1}
C {symbols/cap_mim_2f0fF.sym} 1150 -60 0 0 {name=C3
W=70.7e-6
L=70.7e-6
model=cap_mim_2f0fF
spiceprefix=X
m=1}
C {symbols/cap_mim_2f0fF.sym} 1300 -60 0 0 {name=C4
W=70.7e-6
L=70.7e-6
model=cap_mim_2f0fF
spiceprefix=X
m=1}
C {symbols/cap_mim_2f0fF.sym} 1450 -60 0 0 {name=C5
W=70.7e-6
L=70.7e-6
model=cap_mim_2f0fF
spiceprefix=X
m=1}
C {symbols/cap_mim_2f0fF.sym} 1600 -60 0 0 {name=C6
W=70.7e-6
L=70.7e-6
model=cap_mim_2f0fF
spiceprefix=X
m=1}
C {symbols/cap_mim_2f0fF.sym} 1750 -60 0 0 {name=C7
W=70.7e-6
L=70.7e-6
model=cap_mim_2f0fF
spiceprefix=X
m=1}
C {symbols/cap_mim_2f0fF.sym} 1900 -60 0 0 {name=C8
W=70.7e-6
L=70.7e-6
model=cap_mim_2f0fF
spiceprefix=X
m=1}
C {symbols/cap_mim_2f0fF.sym} 2050 -60 0 0 {name=C9
W=70.7e-6
L=70.7e-6
model=cap_mim_2f0fF
spiceprefix=X
m=1}
C {symbols/cap_mim_2f0fF.sym} 2200 -60 0 0 {name=C10
W=70.7e-6
L=70.7e-6
model=cap_mim_2f0fF
spiceprefix=X
m=1}
C {symbols/cap_mim_2f0fF.sym} 2350 -60 0 0 {name=C11
W=70.7e-6
L=70.7e-6
model=cap_mim_2f0fF
spiceprefix=X
m=1}
C {iopin.sym} -1110 -610 0 1 {name=p15 lab=avdd
}
C {iopin.sym} -1080 400 0 1 {name=p16 lab=avss
}
C {symbols/pfet_03v3.sym} -300 1380 0 0 {name=MTAIL
L=6u
W=28.91u
nf=1
mult=6
m=6
ad="'int((nf+1)/2) * W/nf * 0.18u'"
pd="'2*int((nf+1)/2) * (W/nf + 0.18u)'"
as="'int((nf+2)/2) * W/nf * 0.18u'"
ps="'2*int((nf+2)/2) * (W/nf + 0.18u)'"
nrd="'0.18u / W'" nrs="'0.18u / W'"
sa=0 sb=0 sd=0
model=pfet_03v3
spiceprefix=X
}
C {lab_wire.sym} -340 1380 0 0 {name=p35 sig_type=std_logic lab=vbp_tail
}
C {lab_wire.sym} -330 1470 0 0 {name=p36 sig_type=std_logic lab=avdd
}
C {lab_wire.sym} -190 1470 0 0 {name=p37 sig_type=std_logic lab=avdd
}
C {lab_wire.sym} 160 1780 0 0 {name=p38 sig_type=std_logic lab=avss
}
C {lab_wire.sym} -30 1610 0 0 {name=p39 sig_type=std_logic lab=avss
}
C {lab_wire.sym} 350 1610 0 0 {name=p40 sig_type=std_logic lab=avss
}
C {lab_wire.sym} 160 1270 0 0 {name=p41 sig_type=std_logic lab=avdd
}
C {lab_wire.sym} 10 1330 0 0 {name=p42 sig_type=std_logic lab=avdd
}
C {lab_wire.sym} 320 1330 0 0 {name=p43 sig_type=std_logic lab=avdd
}
C {lab_wire.sym} 180 1610 0 0 {name=p49 sig_type=std_logic lab=vbn_fold
}
C {lab_wire.sym} 180 1720 0 0 {name=p50 sig_type=std_logic lab=vbn_sink
}
C {lab_wire.sym} 170 1450 0 0 {name=p51 sig_type=std_logic lab=vbp_cas
}
C {lab_wire.sym} -330 1410 0 0 {name=p52 sig_type=std_logic lab=vsp
}
C {lab_wire.sym} -320 1670 0 0 {name=p53 sig_type=std_logic lab=xf1
}
C {lab_wire.sym} -120 1650 0 0 {name=p54 sig_type=std_logic lab=xf2
}
C {lab_wire.sym} 60 1500 0 0 {name=p55 sig_type=std_logic lab=y1
}
C {lab_wire.sym} 20 1400 0 0 {name=p56 sig_type=std_logic lab=pm1
}
C {lab_wire.sym} 270 1400 0 0 {name=p57 sig_type=std_logic lab=pm2
}
C {lab_wire.sym} 270 1530 0 0 {name=p58 sig_type=std_logic lab=vgn2
}
C {lab_wire.sym} -440 1470 0 0 {name=p59 sig_type=std_logic lab=v1
}
C {lab_wire.sym} -100 1470 0 0 {name=p60 sig_type=std_logic lab=v2
}
C {lab_wire.sym} 10 1450 0 0 {name=p61 sig_type=std_logic lab=avdd
}
C {lab_wire.sym} 320 1450 0 0 {name=p62 sig_type=std_logic lab=avdd
}
C {lab_wire.sym} 440 600 0 0 {name=p33 sig_type=std_logic lab=avdd
}
C {lab_wire.sym} 730 1170 0 0 {name=p34 sig_type=std_logic lab=avss
}
C {lab_wire.sym} 970 790 0 0 {name=p44 sig_type=std_logic lab=avss
}
C {lab_wire.sym} 970 910 0 0 {name=p45 sig_type=std_logic lab=avss
}
C {lab_wire.sym} 460 950 0 0 {name=p48 sig_type=std_logic lab=vbp_tail
}
C {lab_wire.sym} 870 970 0 0 {name=p63 sig_type=std_logic lab=vbn_sink
}
C {lab_wire.sym} 1100 730 0 0 {name=p64 sig_type=std_logic lab=vbn_fold
}
C {lab_wire.sym} 1090 840 0 0 {name=p65 sig_type=std_logic lab=vnx_bias
}
C {lab_wire.sym} 1340 1020 0 0 {name=p46 sig_type=std_logic lab=vbp_cas
}
C {lab_wire.sym} 1340 810 0 0 {name=p47 sig_type=std_logic lab=vbp_bias
}
C {lab_wire.sym} 410 1080 0 0 {name=p68 sig_type=std_logic lab=vbn_i
}
C {lab_wire.sym} 1220 1100 0 0 {name=p69 sig_type=std_logic lab=vbn_i
}
C {lab_wire.sym} 890 730 0 0 {name=p70 sig_type=std_logic lab=vbp_i
}
C {lab_wire.sym} 1090 680 0 0 {name=p71 sig_type=std_logic lab=vbp_i
}
C {lab_wire.sym} 170 890 0 0 {name=p73 sig_type=std_logic lab=vrs
}
C {lab_wire.sym} 10 750 0 0 {name=p67 sig_type=std_logic lab=vbn_i
}
C {lab_wire.sym} 170 730 0 0 {name=p66 sig_type=std_logic lab=vbp_i
}
C {lab_wire.sym} 210 820 0 0 {name=p72 sig_type=std_logic lab=avss
}
C {lab_wire.sym} 0 820 0 0 {name=p74 sig_type=std_logic lab=avss
}
C {symbols/nwell.sym} 170 1010 0 0 {name=R3
W=2e-6
L=20.19e-6
model=nwell
spiceprefix=X
m=1}
C {symbols/pplus_u.sym} 170 1100 0 0 {name=R4
W=1e-6
L=232.53e-6
model=pplus_u
spiceprefix=X
m=1}
C {lab_wire.sym} 140 1010 0 0 {name=p75 sig_type=std_logic lab=avss
}
C {lab_wire.sym} 140 1100 0 0 {name=p76 sig_type=std_logic lab=avdd
}
C {vsource.sym} 170 940 0 0 {name=VSENSE value=0 savecurrent=false}
C {lab_wire.sym} 530 820 0 1 {name=p77 sig_type=std_logic lab=vsu
}
C {lab_wire.sym} -500 970 0 0 {name=p78 sig_type=std_logic lab=vsu1
}
C {lab_wire.sym} -500 1060 0 0 {name=p79 sig_type=std_logic lab=vsu2
}
C {lab_wire.sym} -430 1010 0 0 {name=p82 sig_type=std_logic lab=vbp_i
}
C {lab_wire.sym} -430 1100 0 0 {name=p83 sig_type=std_logic lab=vbp_i
}
C {vsource.sym} -90 780 3 0 {name=VSTARTSENSE value=0 savecurrent=false}
C {symbols/pfet_05v0.sym} 250 1450 0 0 {name=PCAS2
L=8u
W=22.21u
nf=1
mult=6
m=6
ad="'int((nf+1)/2) * W/nf * 0.18u'"
pd="'2*int((nf+1)/2) * (W/nf + 0.18u)'"
as="'int((nf+2)/2) * W/nf * 0.18u'"
ps="'2*int((nf+2)/2) * (W/nf + 0.18u)'"
nrd="'0.18u / W'" nrs="'0.18u / W'"
sa=0 sb=0 sd=0
model=pfet_05v0
spiceprefix=X
}
C {symbols/pfet_05v0.sym} 40 1450 0 1 {name=PCAS1
L=8u
W=22.21u
nf=1
mult=6
m=6
ad="'int((nf+1)/2) * W/nf * 0.18u'"
pd="'2*int((nf+1)/2) * (W/nf + 0.18u)'"
as="'int((nf+2)/2) * W/nf * 0.18u'"
ps="'2*int((nf+2)/2) * (W/nf + 0.18u)'"
nrd="'0.18u / W'" nrs="'0.18u / W'"
sa=0 sb=0 sd=0
model=pfet_05v0
spiceprefix=X
}
C {symbols/pfet_05v0.sym} -150 1470 0 1 {name=MINN
L=4u
W=54.89u
nf=1
mult=5
m=5
ad="'int((nf+1)/2) * W/nf * 0.18u'"
pd="'2*int((nf+1)/2) * (W/nf + 0.18u)'"
as="'int((nf+2)/2) * W/nf * 0.18u'"
ps="'2*int((nf+2)/2) * (W/nf + 0.18u)'"
nrd="'0.18u / W'" nrs="'0.18u / W'"
sa=0 sb=0 sd=0
model=pfet_05v0
spiceprefix=X
}
C {symbols/pfet_05v0.sym} -410 1470 0 0 {name=MINP
L=4u
W=54.89u
nf=1
mult=5
m=5
ad="'int((nf+1)/2) * W/nf * 0.18u'"
pd="'2*int((nf+1)/2) * (W/nf + 0.18u)'"
as="'int((nf+2)/2) * W/nf * 0.18u'"
ps="'2*int((nf+2)/2) * (W/nf + 0.18u)'"
nrd="'0.18u / W'" nrs="'0.18u / W'"
sa=0 sb=0 sd=0
model=pfet_05v0
spiceprefix=X
}
C {symbols/nfet_05v0.sym} 250 1610 0 0 {name=MFOLD2
L=6u
W=18.49u
nf=1
mult=1
m=1
ad="'int((nf+1)/2) * W/nf * 0.18u'"
pd="'2*int((nf+1)/2) * (W/nf + 0.18u)'"
as="'int((nf+2)/2) * W/nf * 0.18u'"
ps="'2*int((nf+2)/2) * (W/nf + 0.18u)'"
nrd="'0.18u / W'" nrs="'0.18u / W'"
sa=0 sb=0 sd=0
model=nfet_05v0
spiceprefix=X
}
C {symbols/nfet_05v0.sym} 40 1610 0 1 {name=MFOLD1
L=6u
W=18.49u
nf=1
mult=1
m=1
ad="'int((nf+1)/2) * W/nf * 0.18u'"
pd="'2*int((nf+1)/2) * (W/nf + 0.18u)'"
as="'int((nf+2)/2) * W/nf * 0.18u'"
ps="'2*int((nf+2)/2) * (W/nf + 0.18u)'"
nrd="'0.18u / W'" nrs="'0.18u / W'"
sa=0 sb=0 sd=0
model=nfet_05v0
spiceprefix=X
}
C {symbols/nfet_05v0.sym} 30 820 0 1 {name=N1
L=8u
W=7.78u
nf=1
mult=1
m=1
ad="'int((nf+1)/2) * W/nf * 0.18u'"
pd="'2*int((nf+1)/2) * (W/nf + 0.18u)'"
as="'int((nf+2)/2) * W/nf * 0.18u'"
ps="'2*int((nf+2)/2) * (W/nf + 0.18u)'"
nrd="'0.18u / W'" nrs="'0.18u / W'"
sa=0 sb=0 sd=0
model=nfet_05v0
spiceprefix=X
}
C {symbols/nfet_05v0.sym} 150 820 0 0 {name=N2
L=8u
W=9.13u
nf=1
mult=1
m=1
ad="'int((nf+1)/2) * W/nf * 0.18u'"
pd="'2*int((nf+1)/2) * (W/nf + 0.18u)'"
as="'int((nf+2)/2) * W/nf * 0.18u'"
ps="'2*int((nf+2)/2) * (W/nf + 0.18u)'"
nrd="'0.18u / W'" nrs="'0.18u / W'"
sa=0 sb=0 sd=0
model=nfet_05v0
spiceprefix=X
}
C {symbols/pfet_05v0.sym} 150 660 0 0 {name=PREF
L=8u
W=18.75u
nf=1
mult=5
m=5
ad="'int((nf+1)/2) * W/nf * 0.18u'"
pd="'2*int((nf+1)/2) * (W/nf + 0.18u)'"
as="'int((nf+2)/2) * W/nf * 0.18u'"
ps="'2*int((nf+2)/2) * (W/nf + 0.18u)'"
nrd="'0.18u / W'" nrs="'0.18u / W'"
sa=0 sb=0 sd=0
model=pfet_05v0
spiceprefix=X
}
C {symbols/pfet_05v0.sym} 30 660 0 1 {name=PRMIR
L=8u
W=18.75u
nf=1
mult=5
m=5
ad="'int((nf+1)/2) * W/nf * 0.18u'"
pd="'2*int((nf+1)/2) * (W/nf + 0.18u)'"
as="'int((nf+2)/2) * W/nf * 0.18u'"
ps="'2*int((nf+2)/2) * (W/nf + 0.18u)'"
nrd="'0.18u / W'" nrs="'0.18u / W'"
sa=0 sb=0 sd=0
model=pfet_05v0
spiceprefix=X
}
C {symbols/nfet_05v0.sym} 440 1080 0 0 {name=NTAIL
L=8u
W=13.95u
nf=1
m=1
ad="'int((nf+1)/2) * W/nf * 0.18u'"
pd="'2*int((nf+1)/2) * (W/nf + 0.18u)'"
as="'int((nf+2)/2) * W/nf * 0.18u'"
ps="'2*int((nf+2)/2) * (W/nf + 0.18u)'"
nrd="'0.18u / W'" nrs="'0.18u / W'"
sa=0 sb=0 sd=0
model=nfet_05v0
spiceprefix=X
}
C {symbols/nfet_05v0.sym} 1250 1100 0 0 {name=N3
L=8u
W=0.65u
nf=1
m=1
ad="'int((nf+1)/2) * W/nf * 0.18u'"
pd="'2*int((nf+1)/2) * (W/nf + 0.18u)'"
as="'int((nf+2)/2) * W/nf * 0.18u'"
ps="'2*int((nf+2)/2) * (W/nf + 0.18u)'"
nrd="'0.18u / W'" nrs="'0.18u / W'"
sa=0 sb=0 sd=0
model=nfet_05v0
spiceprefix=X
}
C {symbols/pfet_05v0.sym} 810 730 0 1 {name=MPSINK
L=8u
W=18.95u
nf=1
mult=17
m=17
ad="'int((nf+1)/2) * W/nf * 0.18u'"
pd="'2*int((nf+1)/2) * (W/nf + 0.18u)'"
as="'int((nf+2)/2) * W/nf * 0.18u'"
ps="'2*int((nf+2)/2) * (W/nf + 0.18u)'"
nrd="'0.18u / W'" nrs="'0.18u / W'"
sa=0 sb=0 sd=0
model=pfet_05v0
spiceprefix=X
}
C {symbols/pfet_05v0.sym} 1020 680 0 1 {name=MPFOLD
L=8u
W=18.99u
nf=1
mult=12
m=12
ad="'int((nf+1)/2) * W/nf * 0.18u'"
pd="'2*int((nf+1)/2) * (W/nf + 0.18u)'"
as="'int((nf+2)/2) * W/nf * 0.18u'"
ps="'2*int((nf+2)/2) * (W/nf + 0.18u)'"
nrd="'0.18u / W'" nrs="'0.18u / W'"
sa=0 sb=0 sd=0
model=pfet_05v0
spiceprefix=X
}
C {symbols/nfet_05v0.sym} 1020 790 0 1 {name=VBNFOLDHIGH
L=6u
W=4.62u
nf=1
m=1
mult=1
ad="'int((nf+1)/2) * W/nf * 0.18u'"
pd="'2*int((nf+1)/2) * (W/nf + 0.18u)'"
as="'int((nf+2)/2) * W/nf * 0.18u'"
ps="'2*int((nf+2)/2) * (W/nf + 0.18u)'"
nrd="'0.18u / W'" nrs="'0.18u / W'"
sa=0 sb=0 sd=0
model=nfet_05v0
spiceprefix=X
}
C {symbols/pfet_05v0.sym} 1290 940 0 1 {name=VBPCASLOW
L=8u
W=18.93u
nf=1
mult=10
m=10
ad="'int((nf+1)/2) * W/nf * 0.18u'"
pd="'2*int((nf+1)/2) * (W/nf + 0.18u)'"
as="'int((nf+2)/2) * W/nf * 0.18u'"
ps="'2*int((nf+2)/2) * (W/nf + 0.18u)'"
nrd="'0.18u / W'" nrs="'0.18u / W'"
sa=0 sb=0 sd=0
model=pfet_05v0
spiceprefix=X
}
C {symbols/pfet_03v3.sym} 480 700 0 1 {name=VBPTAIL
L=6u
W=13.75u
nf=1
mult=3
m=3
ad="'int((nf+1)/2) * W/nf * 0.18u'"
pd="'2*int((nf+1)/2) * (W/nf + 0.18u)'"
as="'int((nf+2)/2) * W/nf * 0.18u'"
ps="'2*int((nf+2)/2) * (W/nf + 0.18u)'"
nrd="'0.18u / W'" nrs="'0.18u / W'"
sa=0 sb=0 sd=0
model=pfet_03v3
spiceprefix=X
}
C {symbols/nfet_03v3.sym} 1020 910 0 1 {name=VBNFOLDLOW
L=8u
W=1.62u
nf=1
m=1
mult=1
ad="'int((nf+1)/2) * W/nf * 0.18u'"
pd="'2*int((nf+1)/2) * (W/nf + 0.18u)'"
as="'int((nf+2)/2) * W/nf * 0.18u'"
ps="'2*int((nf+2)/2) * (W/nf + 0.18u)'"
nrd="'0.18u / W'" nrs="'0.18u / W'"
sa=0 sb=0 sd=0
model=nfet_03v3
spiceprefix=X
}
C {symbols/pfet_03v3.sym} 1290 740 0 1 {name=VBPCASHIGHER
L=8u
W=19.06u
nf=1
mult=9
m=9
ad="'int((nf+1)/2) * W/nf * 0.18u'"
pd="'2*int((nf+1)/2) * (W/nf + 0.18u)'"
as="'int((nf+2)/2) * W/nf * 0.18u'"
ps="'2*int((nf+2)/2) * (W/nf + 0.18u)'"
nrd="'0.18u / W'" nrs="'0.18u / W'"
sa=0 sb=0 sd=0
model=pfet_03v3
spiceprefix=X
}
C {symbols/nfet_05v0.sym} -480 1010 0 1 {name=SUPN2
L=50u
W=0.5u
nf=1
mult=1
m=1
ad="'int((nf+1)/2) * W/nf * 0.18u'"
pd="'2*int((nf+1)/2) * (W/nf + 0.18u)'"
as="'int((nf+2)/2) * W/nf * 0.18u'"
ps="'2*int((nf+2)/2) * (W/nf + 0.18u)'"
nrd="'0.18u / W'" nrs="'0.18u / W'"
sa=0 sb=0 sd=0
model=nfet_05v0
spiceprefix=X
}
C {symbols/nfet_05v0.sym} -480 1100 0 1 {name=SUPN3
L=50u
W=0.5u
nf=1
mult=1
m=1
ad="'int((nf+1)/2) * W/nf * 0.18u'"
pd="'2*int((nf+1)/2) * (W/nf + 0.18u)'"
as="'int((nf+2)/2) * W/nf * 0.18u'"
ps="'2*int((nf+2)/2) * (W/nf + 0.18u)'"
nrd="'0.18u / W'" nrs="'0.18u / W'"
sa=0 sb=0 sd=0
model=nfet_05v0
spiceprefix=X
}
C {symbols/pfet_05v0.sym} 40 1330 0 1 {name=PLOAD1
L=4u
W=20.76u
nf=1
mult=6
m=6
ad="'int((nf+1)/2) * W/nf * 0.18u'"
pd="'2*int((nf+1)/2) * (W/nf + 0.18u)'"
as="'int((nf+2)/2) * W/nf * 0.18u'"
ps="'2*int((nf+2)/2) * (W/nf + 0.18u)'"
nrd="'0.18u / W'" nrs="'0.18u / W'"
sa=0 sb=0 sd=0
model=pfet_05v0
spiceprefix=X
}
C {symbols/pfet_05v0.sym} 250 1330 0 0 {name=PLOAD2
L=4u
W=20.76u
nf=1
mult=6
m=6
ad="'int((nf+1)/2) * W/nf * 0.18u'"
pd="'2*int((nf+1)/2) * (W/nf + 0.18u)'"
as="'int((nf+2)/2) * W/nf * 0.18u'"
ps="'2*int((nf+2)/2) * (W/nf + 0.18u)'"
nrd="'0.18u / W'" nrs="'0.18u / W'"
sa=0 sb=0 sd=0
model=pfet_05v0
spiceprefix=X
}
C {symbols/nfet_05v0.sym} 0 1530 0 0 {name=MFOLD1C
L=6u
W=18.49u
nf=1
mult=1
m=1
ad="'int((nf+1)/2) * W/nf * 0.18u'"
pd="'2*int((nf+1)/2) * (W/nf + 0.18u)'"
as="'int((nf+2)/2) * W/nf * 0.18u'"
ps="'2*int((nf+2)/2) * (W/nf + 0.18u)'"
nrd="'0.18u / W'" nrs="'0.18u / W'"
sa=0 sb=0 sd=0
model=nfet_05v0
spiceprefix=X
}
C {lab_wire.sym} 40 1530 0 0 {name=psrg5_label9 sig_type=std_logic lab=avss}
C {lab_wire.sym} 20 1570 0 0 {name=psrg5_label10 sig_type=std_logic lab=psrg_mf1_protected}
C {lab_wire.sym} -30 1530 0 0 {name=psrg1 sig_type=std_logic lab=psrg_vnc}
C {symbols/pfet_05v0.sym} -720 660 0 1 {name=RB_P
L=4u
W=17.74u
nf=1
mult=7
m=7
ad="'int((nf+1)/2) * W/nf * 0.18u'"
pd="'2*int((nf+1)/2) * (W/nf + 0.18u)'"
as="'int((nf+2)/2) * W/nf * 0.18u'"
ps="'2*int((nf+2)/2) * (W/nf + 0.18u)'"
nrd="'0.18u / W'" nrs="'0.18u / W'"
sa=0 sb=0 sd=0
model=pfet_05v0
spiceprefix=X
}
C {symbols/nfet_05v0.sym} -760 890 0 0 {name=RB_NU
L=20u
W=0.71u
nf=1
mult=1
m=1
ad="'int((nf+1)/2) * W/nf * 0.18u'"
pd="'2*int((nf+1)/2) * (W/nf + 0.18u)'"
as="'int((nf+2)/2) * W/nf * 0.18u'"
ps="'2*int((nf+2)/2) * (W/nf + 0.18u)'"
nrd="'0.18u / W'" nrs="'0.18u / W'"
sa=0 sb=0 sd=0
model=nfet_05v0
spiceprefix=X
}
C {symbols/nfet_05v0.sym} -760 1120 0 0 {name=RB_NL
L=20u
W=0.54u
nf=1
mult=1
m=1
ad="'int((nf+1)/2) * W/nf * 0.18u'"
pd="'2*int((nf+1)/2) * (W/nf + 0.18u)'"
as="'int((nf+2)/2) * W/nf * 0.18u'"
ps="'2*int((nf+2)/2) * (W/nf + 0.18u)'"
nrd="'0.18u / W'" nrs="'0.18u / W'"
sa=0 sb=0 sd=0
model=nfet_05v0
spiceprefix=X
}
C {lab_wire.sym} -630 660 0 0 {name=rb_pg lab=vbp_i}
C {lab_wire.sym} -740 790 0 0 {name=rb_vnc lab=psrg_vnc}
C {lab_wire.sym} -630 890 0 0 {name=rb_nb1 lab=avss}
C {lab_wire.sym} -740 1020 0 0 {name=rb_mid_label lab=rb_mid}
C {symbols/pfet_05v0.sym} 320 810 0 1 {name=MSU_LOAD
W=1u L=8u nf=1 m=1 mult=1
ad="'int((nf+1)/2) * W/nf * 0.18u'"
pd="'2*int((nf+1)/2) * (W/nf + 0.18u)'"
as="'int((nf+2)/2) * W/nf * 0.18u'"
ps="'2*int((nf+2)/2) * (W/nf + 0.18u)'"
nrd="'0.18u / W'" nrs="'0.18u / W'"
sa=0 sb=0 sd=0 model=pfet_05v0 spiceprefix=X}
C {lab_wire.sym} 300 900 0 1 {name=MSU_LOAD_p0 lab=su_state}
C {lab_wire.sym} 260 810 0 1 {name=MSU_LOAD_p3 lab=avdd}
C {symbols/pfet_05v0.sym} 600 820 0 0 {name=MSU_HYS
W=1u L=8u nf=1 m=1 mult=1
ad="'int((nf+1)/2) * W/nf * 0.18u'"
pd="'2*int((nf+1)/2) * (W/nf + 0.18u)'"
as="'int((nf+2)/2) * W/nf * 0.18u'"
ps="'2*int((nf+2)/2) * (W/nf + 0.18u)'"
nrd="'0.18u / W'" nrs="'0.18u / W'"
sa=0 sb=0 sd=0 model=pfet_05v0 spiceprefix=X}
C {lab_wire.sym} 630 820 0 1 {name=MSU_HYS_p3 lab=avdd}
C {symbols/nfet_05v0.sym} 320 980 0 1 {name=MSU_SENSE
W=4u L=1u nf=1 m=1 mult=1
ad="'int((nf+1)/2) * W/nf * 0.18u'"
pd="'2*int((nf+1)/2) * (W/nf + 0.18u)'"
as="'int((nf+2)/2) * W/nf * 0.18u'"
ps="'2*int((nf+2)/2) * (W/nf + 0.18u)'"
nrd="'0.18u / W'" nrs="'0.18u / W'"
sa=0 sb=0 sd=0 model=nfet_05v0 spiceprefix=X}
C {lab_wire.sym} 380 980 0 1 {name=MSU_SENSE_p1 lab=vgn2}
C {lab_wire.sym} 260 980 0 1 {name=MSU_SENSE_p3 lab=avss}
C {symbols/cap_mim_2f0fF.sym} 470 1620 0 0 {name=C1
W=59e-6
L=59e-6
model=cap_mim_2f0fF
spiceprefix=X
m=1}
C {iopin.sym} 2380 -150 0 0 {name=p88 lab=vref
}
C {symbols/pfet_05v0.sym} -740 -280 0 0 {name=M20
L=8u
W=0.5u
nf=1
m=1
ad="'int((nf+1)/2) * W/nf * 0.18u'"
pd="'2*int((nf+1)/2) * (W/nf + 0.18u)'"
as="'int((nf+2)/2) * W/nf * 0.18u'"
ps="'2*int((nf+2)/2) * (W/nf + 0.18u)'"
nrd="'0.18u / W'" nrs="'0.18u / W'"
sa=0 sb=0 sd=0
model=pfet_05v0
spiceprefix=X
}
C {symbols/pfet_05v0.sym} -580 660 0 0 {name=SUPPDET
L=1u
W=80u
nf=1
m=2
ad="'int((nf+1)/2) * W/nf * 0.18u'"
as="'int((nf+2)/2) * W/nf * 0.18u'"
pd="'2*int((nf+1)/2) * (W/nf + 0.18u)'"
ps="'2*int((nf+2)/2) * (W/nf + 0.18u)'"
nrd="'0.18u / W'"
nrs="'0.18u / W'"
sa=0 sb=0 sd=0
model=pfet_05v0
spiceprefix=X
}
C {symbols/nfet_05v0.sym} -480 850 0 1 {name=SUPN1
L=50u
W=0.5u
nf=1
m=1
ad="'int((nf+1)/2) * W/nf * 0.18u'"
pd="'2*int((nf+1)/2) * (W/nf + 0.18u)'"
as="'int((nf+2)/2) * W/nf * 0.18u'"
ps="'2*int((nf+2)/2) * (W/nf + 0.18u)'"
nrd="'0.18u / W'" nrs="'0.18u / W'"
sa=0 sb=0 sd=0
model=nfet_05v0
spiceprefix=X
}
C {lab_pin.sym} -540 850 0 0 {name=repair_SUPN1_3 lab=avss}
C {symbols/pfet_05v0.sym} -350 730 0 0 {name=SUPINJ
L=8u
W=0.5u
nf=1
m=1
ad="'int((nf+1)/2) * W/nf * 0.18u'"
pd="'2*int((nf+1)/2) * (W/nf + 0.18u)'"
as="'int((nf+2)/2) * W/nf * 0.18u'"
ps="'2*int((nf+2)/2) * (W/nf + 0.18u)'"
nrd="'0.18u / W'" nrs="'0.18u / W'"
sa=0 sb=0 sd=0
model=pfet_05v0
spiceprefix=X
}
C {symbols/pfet_05v0.sym} 160 -100 0 0 {name=M7
L=2u
W=2u
nf=1
m=1
ad="'int((nf+1)/2) * W/nf * 0.18u'"
pd="'2*int((nf+1)/2) * (W/nf + 0.18u)'"
as="'int((nf+2)/2) * W/nf * 0.18u'"
ps="'2*int((nf+2)/2) * (W/nf + 0.18u)'"
nrd="'0.18u / W'" nrs="'0.18u / W'"
sa=0 sb=0 sd=0
model=pfet_05v0
spiceprefix=X}
C {symbols/nfet_05v0.sym} 40 1720 0 1 {name=MSINK1
L=8u
W=16.34u
nf=1
m=6
ad="'int((nf+1)/2) * W/nf * 0.18u'"
pd="'2*int((nf+1)/2) * (W/nf + 0.18u)'"
as="'int((nf+2)/2) * W/nf * 0.18u'"
ps="'2*int((nf+2)/2) * (W/nf + 0.18u)'"
nrd="'0.18u / W'" nrs="'0.18u / W'"
sa=0 sb=0 sd=0
model=nfet_05v0
spiceprefix=X
}
C {symbols/nfet_05v0.sym} 250 1720 0 0 {name=MSINK2
L=8u
W=16.34u
nf=1
m=6
ad="'int((nf+1)/2) * W/nf * 0.18u'"
pd="'2*int((nf+1)/2) * (W/nf + 0.18u)'"
as="'int((nf+2)/2) * W/nf * 0.18u'"
ps="'2*int((nf+2)/2) * (W/nf + 0.18u)'"
nrd="'0.18u / W'" nrs="'0.18u / W'"
sa=0 sb=0 sd=0
model=nfet_05v0
spiceprefix=X
}
C {symbols/nfet_05v0.sym} 810 1050 0 1 {name=VBNSINK
L=8u
W=12.31u
nf=1
m=2
ad="'int((nf+1)/2) * W/nf * 0.18u'"
pd="'2*int((nf+1)/2) * (W/nf + 0.18u)'"
as="'int((nf+2)/2) * W/nf * 0.18u'"
ps="'2*int((nf+2)/2) * (W/nf + 0.18u)'"
nrd="'0.18u / W'" nrs="'0.18u / W'"
sa=0 sb=0 sd=0
model=nfet_05v0
spiceprefix=X
}
C {symbols/pfet_05v0.sym} -840 -540 0 0 {name=AP
L=10u
W=0.5u
nf=1
m=1
ad="'int((nf+1)/2) * W/nf * 0.18u'"
pd="'2*int((nf+1)/2) * (W/nf + 0.18u)'"
as="'int((nf+2)/2) * W/nf * 0.18u'"
ps="'2*int((nf+2)/2) * (W/nf + 0.18u)'"
nrd="'0.18u / W'" nrs="'0.18u / W'"
sa=0 sb=0 sd=0
model=pfet_05v0
spiceprefix=X
}
C {symbols/nfet_05v0.sym} -160 950 0 1 {name=AN
L=8u
W=1u
nf=1
m=1
ad="'int((nf+1)/2) * W/nf * 0.18u'"
as="'int((nf+2)/2) * W/nf * 0.18u'"
pd="'2*int((nf+1)/2) * (W/nf + 0.18u)'"
ps="'2*int((nf+2)/2) * (W/nf + 0.18u)'"
nrd="'0.18u / W'"
nrs="'0.18u / W'"
sa=0 sb=0 sd=0
model=nfet_05v0
spiceprefix=X
}
C {lab_wire.sym} -380 850 0 0 {name=p5 sig_type=std_logic lab=vbp_i
}
C {lab_wire.sym} -500 800 0 0 {name=p80 sig_type=std_logic lab=iref_gate
}
C {lab_wire.sym} -170 780 0 0 {name=p81 sig_type=std_logic lab=net5
}
C {lab_wire.sym} -660 -280 0 0 {name=p89 sig_type=std_logic lab=avdd}
C {lab_wire.sym} 120 -100 0 0 {name=p90 sig_type=std_logic lab=aux_gate}
C {lab_wire.sym} -820 -340 0 0 {name=p91 sig_type=std_logic lab=aux_gate}
C {lab_wire.sym} -180 880 0 0 {name=p92 sig_type=std_logic lab=aux_gate}
C {lab_wire.sym} -80 950 0 0 {name=p93 sig_type=std_logic lab=vbn_i
}
C {lab_wire.sym} 260 -100 0 0 {name=p94 sig_type=std_logic lab=avdd
}

T {LOOP-PROBE CORE: based on the repaired, untrimmed Bandgap_Core.
Only M3's gate and N2's gate are cut; close both external probes at DC.
C1 and the other vgn2 loads stay on MAIN e. Trim circuitry is not included.} -1000 1910 0 0 0.3 0.3 {}
C {iopin.sym} 470 1540 0 0 {name=port_lg_main_e lab=vgn2}
C {iopin.sym} 550 80 0 1 {name=port_lg_main_f lab=lg_main_f}
C {iopin.sym} 80 760 0 0 {name=port_lg_bias_e lab=vbn_i}
C {iopin.sym} 110 820 0 1 {name=port_lg_bias_f lab=lg_bias_f}
